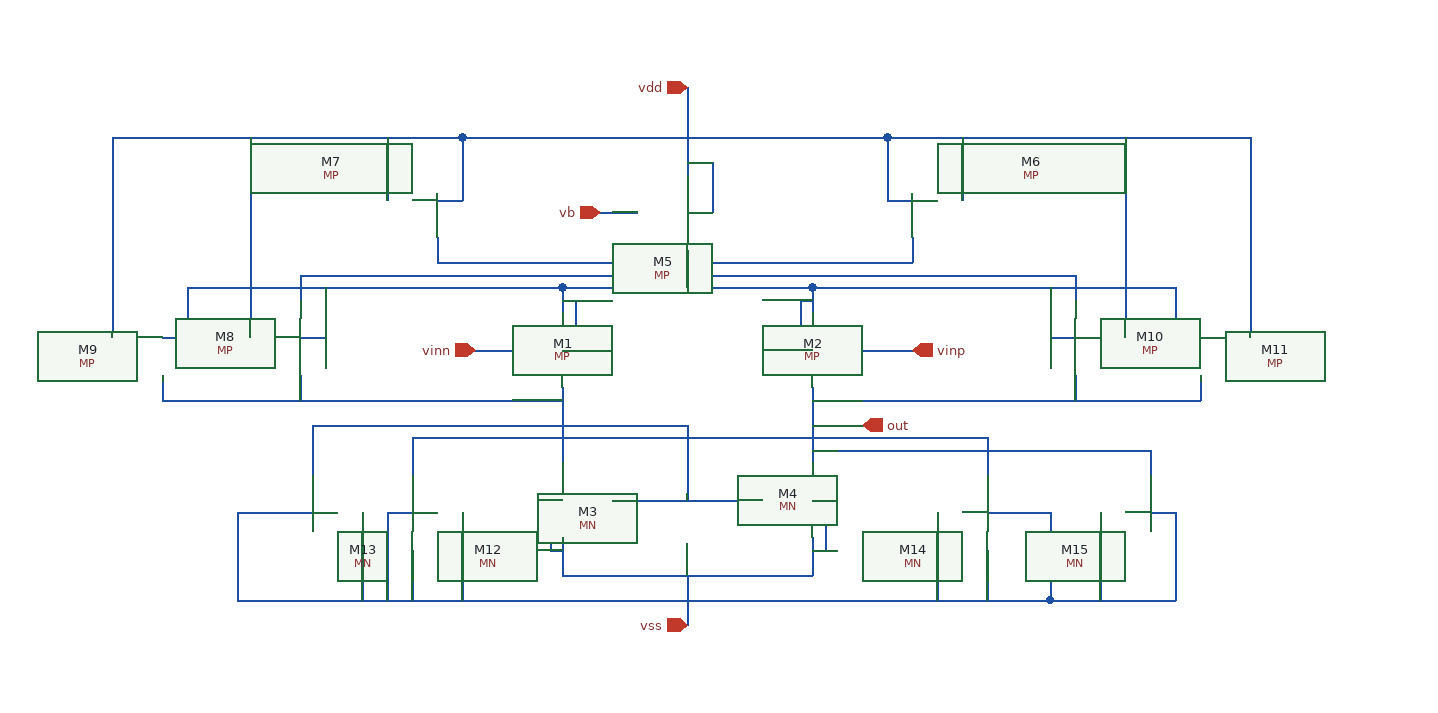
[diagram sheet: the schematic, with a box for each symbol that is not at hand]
v {xschem version=3.4.8RC file_version=1.3}
G {}
K {}
V {}
S {}
F {}
E {}
N 420 -210 420 -150 {
lab=out}
N 220 -210 220 -150 {
lab=#net1}
N 260 -120 380 -120 {
lab=#net1}
N 220 -90 220 -60 {
lab=vss}
N 220 -60 420 -60 {
lab=vss}
N 420 -90 420 -60 {
lab=vss}
N 220 -180 320 -180 {
lab=#net1}
N 320 -180 320 -120 {
lab=#net1}
N 220 -290 420 -290 {
lab=#net2}
N 420 -290 420 -270 {
lab=#net2}
N 320 -320 320 -290 {
lab=#net2}
N 320 -60 320 -30 {
lab=vss}
N 320 -400 320 -380 {
lab=vdd}
N 250 -350 280 -350 {
lab=vb}
N 420 -180 460 -180 {
lab=out}
N 220 -290 220 -270 {
lab=#net2}
N 320 -350 340 -350 {
lab=vdd}
N 340 -390 340 -350 {
lab=vdd}
N 320 -390 340 -390 {
lab=vdd}
N 210 -120 220 -120 {
lab=vss}
N 210 -120 210 -80 {
lab=vss}
N 210 -80 220 -80 {
lab=vss}
N 420 -120 430 -120 {
lab=vss}
N 430 -120 430 -80 {
lab=vss}
N 420 -80 430 -80 {
lab=vss}
N 220 -240 230 -240 {
lab=#net2}
N 230 -280 230 -240 {
lab=#net2}
N 220 -280 230 -280 {
lab=#net2}
N 410 -240 420 -240 {
lab=#net2}
N 410 -280 410 -240 {
lab=#net2}
N 410 -280 420 -280 {
lab=#net2}
N 150 -240 180 -240 {
lab=vinn}
N 460 -240 500 -240 {
lab=vinp}
N 320 -30 320 -20 {
lab=vss}
N 320 -450 320 -400 {
lab=vdd}
N 20 -180 20 -140 {
lab=#net1}
N 20 -180 220 -180 {
lab=#net1}
N -40 -110 20 -110 {
lab=vss}
N -40 -110 -40 -40 {
lab=vss}
N -40 -40 320 -40 {
lab=vss}
N 560 -110 610 -110 {
lab=vss}
N 610 -110 610 -40 {
lab=vss}
N 320 -40 610 -40 {
lab=vss}
N 80 -110 100 -110 {
lab=vss}
N 80 -110 80 -40 {
lab=vss}
N 690 -160 690 -140 {
lab=out}
N 690 -110 710 -110 {
lab=vss}
N 710 -110 710 -40 {
lab=vss}
N 610 -40 710 -40 {
lab=vss}
N 100 -80 100 -40 {
lab=vss}
N 560 -80 560 -40 {
lab=vss}
N 100 -160 100 -140 {
lab=#net3}
N 100 -170 560 -170 {
lab=#net3}
N 100 -170 100 -160 {
lab=#net3}
N 420 -160 690 -160 {
lab=out}
N 560 -170 560 -140 {
lab=#net3}
N 120 -330 120 -310 {
lab=#net2}
N 120 -310 320 -310 {
lab=#net2}
N 320 -310 500 -310 {
lab=#net2}
N 500 -330 500 -310 {
lab=#net2}
N 120 -360 140 -360 {
lab=vdd}
N 140 -410 140 -360 {
lab=vdd}
N 140 -410 320 -410 {
lab=vdd}
N 320 -410 480 -410 {
lab=vdd}
N 480 -410 480 -360 {
lab=vdd}
N 480 -360 500 -360 {
lab=vdd}
N -100 -220 -100 -200 {
lab=#net1}
N -100 -200 220 -200 {
lab=#net1}
N 420 -200 730 -200 {
lab=out}
N 730 -220 730 -200 {
lab=out}
N 630 -220 630 -200 {
lab=out}
N 10 -220 10 -200 {
lab=#net1}
N -80 -290 220 -290 {
lab=#net2}
N -80 -290 -80 -250 {
lab=#net2}
N -100 -250 -80 -250 {
lab=#net2}
N 10 -250 30 -250 {
lab=#net2}
N 30 -290 30 -250 {
lab=#net2}
N 420 -290 710 -290 {
lab=#net2}
N 710 -290 710 -250 {
lab=#net2}
N 710 -250 730 -250 {
lab=#net2}
N 610 -250 630 -250 {
lab=#net2}
N 610 -290 610 -250 {
lab=#net2}
N 10 -300 10 -280 {
lab=#net4}
N 10 -300 630 -300 {
lab=#net4}
N 630 -300 630 -280 {
lab=#net4}
N 480 -410 650 -410 {
lab=vdd}
N 60 -410 140 -410 {
lab=vdd}
N 80 -410 80 -360 {
lab=vdd}
N 540 -410 540 -360 {
lab=vdd}
N -140 -410 60 -410 {
lab=vdd}
N -140 -410 -140 -250 {
lab=vdd}
N 650 -410 770 -410 {
lab=vdd}
N 770 -410 770 -250 {
lab=vdd}
N -30 -410 -30 -250 {
lab=vdd}
N 670 -410 670 -250 {
lab=vdd}
N 650 -110 650 -40 {
lab=vss}
N 520 -110 520 -40 {
lab=vss}
N 140 -110 140 -40 {
lab=vss}
N 60 -110 60 -40 {
lab=vss}
C {devices/ipin.sym} 150 -240 0 0 {name=p9 lab=vinn}
C {devices/ipin.sym} 500 -240 0 1 {name=p5 lab=vinp}
C {devices/ipin.sym} 250 -350 0 0 {name=p2 lab=vb}
C {devices/opin.sym} 460 -180 0 0 {name=p3 lab=out}
C {devices/iopin.sym} 320 -450 0 0 {name=p1 lab=vdd
}
C {devices/iopin.sym} 320 -20 0 0 {name=p4 lab=vss
}
C {MP.sym} 280 -350 0 0 {name=M5 model=PMOS w=180u l=1u m=1 as=0 ad=0 ps=0 pd=0 nrd=0 nrs=0 spiceprefix=X}
C {MP.sym} 180 -240 0 0 {name=M1 model=PMOS w=360u l=1u m=1 as=0 ad=0 ps=0 pd=0 nrd=0 nrs=0 spiceprefix=X}
C {MP.sym} 460 -240 0 1 {name=M2 model=PMOS w=360u l=1u m=1 as=0 ad=0 ps=0 pd=0 nrd=0 nrs=0 spiceprefix=X}
C {MN.sym} 260 -120 0 1 {name=M3 model=NMOS w=30u l=1u m=1 as=0 ad=0 ps=0 pd=0 nrd=0 nrs=0 spiceprefix=X}
C {MN.sym} 380 -120 0 0 {name=M4 model=NMOS w=30u l=1u m=1 as=0 ad=0 ps=0 pd=0 nrd=0 nrs=0 spiceprefix=X}
C {MP.sym} 540 -360 0 1 {name=M6 model=PMOS w=10u l=1u m=1 as=0 ad=0 ps=0 pd=0 nrd=0 nrs=0 spiceprefix=X}
C {MP.sym} 80 -360 0 0 {name=M7 model=PMOS w=10u l=1u m=1 as=0 ad=0 ps=0 pd=0 nrd=0 nrs=0 spiceprefix=X}
C {MP.sym} -30 -250 0 0 {name=M8 model=PMOS w=10u l=1u m=1 as=0 ad=0 ps=0 pd=0 nrd=0 nrs=0 spiceprefix=X}
C {MP.sym} -140 -250 0 0 {name=M9 model=PMOS w=10u l=1u m=1 as=0 ad=0 ps=0 pd=0 nrd=0 nrs=0 spiceprefix=X}
C {MP.sym} 670 -250 0 1 {name=M10 model=PMOS w=10u l=1u m=1 as=0 ad=0 ps=0 pd=0 nrd=0 nrs=0 spiceprefix=X}
C {MP.sym} 770 -250 0 1 {name=M11 model=PMOS w=10u l=1u m=1 as=0 ad=0 ps=0 pd=0 nrd=0 nrs=0 spiceprefix=X}
C {MN.sym} 140 -110 0 1 {name=M12 model=NMOS w=10u l=1u m=1 as=0 ad=0 ps=0 pd=0 nrd=0 nrs=0 spiceprefix=X}
C {MN.sym} 60 -110 0 1 {name=M13 model=NMOS w=10u l=1u m=1 as=0 ad=0 ps=0 pd=0 nrd=0 nrs=0 spiceprefix=X}
C {MN.sym} 520 -110 0 0 {name=M14 model=NMOS w=10u l=1u m=1 as=0 ad=0 ps=0 pd=0 nrd=0 nrs=0 spiceprefix=X}
C {MN.sym} 650 -110 0 0 {name=M15 model=NMOS w=10u l=1u m=1 as=0 ad=0 ps=0 pd=0 nrd=0 nrs=0 spiceprefix=X}
